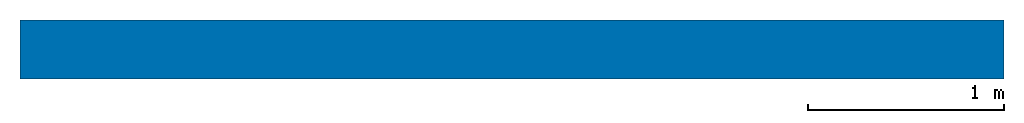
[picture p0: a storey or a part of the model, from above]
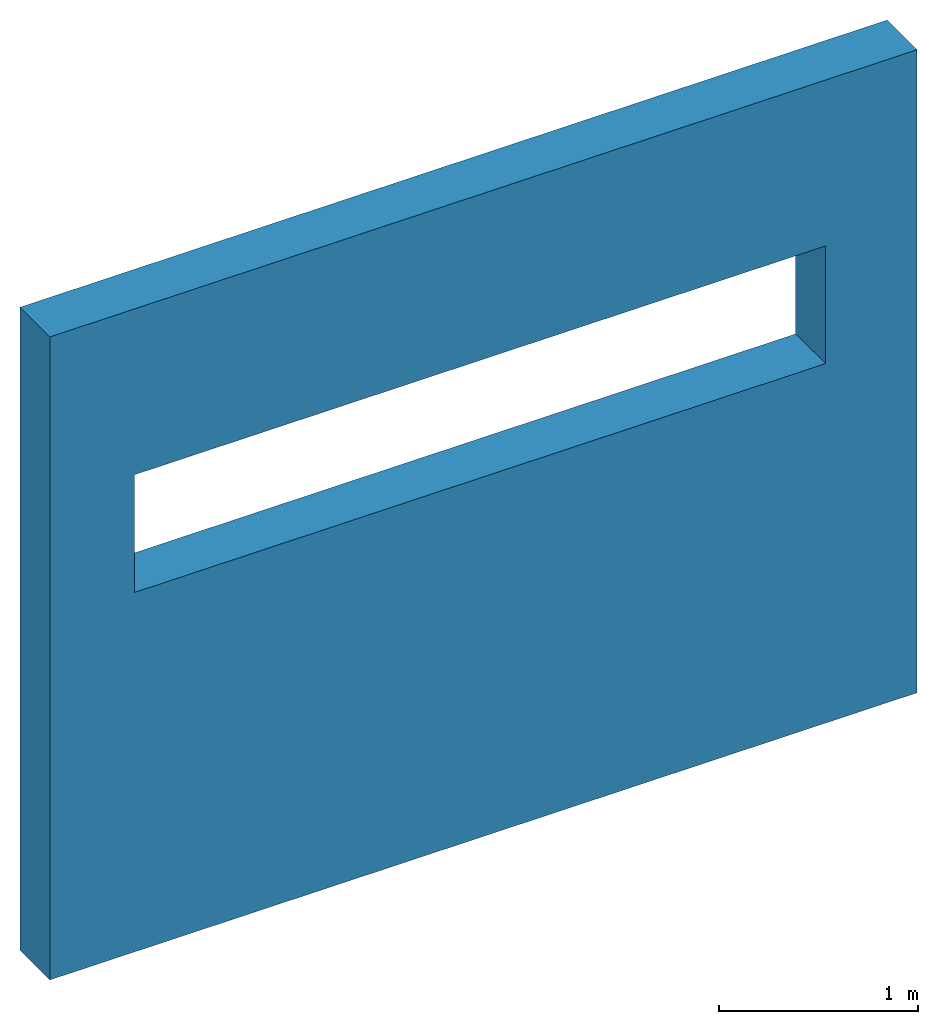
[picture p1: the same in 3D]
Properties of the parts of a building model (IFC2X3)

# File
Description: ViewDefinition [CoordinationView_V2.0, QuantityTakeOffAddOnView]
File name: P294-PE-ARQ_Moduls.ifc (Edited by Simplebim 8.2 SR1 - Evaluation)
Time: 2020-10-28T11:02:44
Written by: The EXPRESS Data Manager Version 5.02.0100.07 : 28 Aug 2013
Made in: 20191031_1115(x64) - Exporter 20.2.0.48 - Alternate UI 20.2.0.48

# IfcProject, P294
LongName: EDIFICI HOSPITALARI POLIVALENT Hospital Universitari Arnau de Vilanova; Phase: PROJECTE EXECUTIU

# IfcSite, Default
RefLatitude: 41, 36, 50, 998535; RefLongitude: 0, 37, 32, 890777; RefElevation: 175 m
Other - Project Address: Carrer de l'Arquitecte Gomà, 10 Lleida 25196; Project Number: P294; Category: Project Information; Project Status: PROJECTE EXECUTIU; Project Issue Date: SETEMBRE 2020; Client Name: SERVEI CATALÀ DE LA SALUT; Project Name: EDIFICI HOSPITALARI POLIVALENT Hospital Universitari Arnau de Vilanova
Identity Data - Autor 4: JOANA CORNUDELLA; Autor 2: MAXIMIÀ TORRUELLA; Autor 3: LUIS GOTOR; Autor 1: PATRICIO MARTÍNEZ; Workset: Project Info; Organization Description: Forward Thinking Healthcare Architecture; Author: PMMT Forward Thinking Healthcare Architecture; Organization Name: PMMT
Data - Colaborador 2: EINESA; Constructora: CONSTRUCTORA D'ARO; Colaborador 1: BIS STRUCTURES

# IfcBuilding
Pset_BuildingCommon - NumberOfStoreys: 6
Identity Data - Autor 4: JOANA CORNUDELLA; Autor 2: MAXIMIÀ TORRUELLA; Autor 3: LUIS GOTOR; Autor 1: PATRICIO MARTÍNEZ; Workset: Project Info; Organization Description: Forward Thinking Healthcare Architecture; Author: PMMT Forward Thinking Healthcare Architecture; Organization Name: PMMT
Other - Project Address: Carrer de l'Arquitecte Gomà, 10 Lleida 25196; Project Number: P294; Category: Project Information; Project Status: PROJECTE EXECUTIU; Project Issue Date: SETEMBRE 2020; Client Name: SERVEI CATALÀ DE LA SALUT; Project Name: EDIFICI HOSPITALARI POLIVALENT Hospital Universitari Arnau de Vilanova
Data - Colaborador 2: EINESA; Constructora: CONSTRUCTORA D'ARO; Colaborador 1: BIS STRUCTURES
Pset_ProductRequirements - Category: Project Information

# IfcBuildingStorey: Level:ARCH-NIV-General, P00
LongName: P00; Elevation: 0 m
Identity Data(Type) - Workset: Level Types; Type Name: ARCH-NIV-General
Other - Type Id: Level: ARCH-NIV-General; Type: Level: ARCH-NIV-General; Family and Type: Level: ARCH-NIV-General; Family: Level: ARCH-NIV-General; Category: Levels
Pset_ProductRequirements - Name: P00; Category: Levels
Pset_AirSideSystemInformation - Name: P00
Graphics(Type) - Symbol: ARCH-NIV-Etiqueta: 2mm; Line Pattern: ARCH-DASHDOT1; Symbol at End 1 Default: yes; Symbol at End 2 Default: no; Color: 8421504; Line Weight: 1
Constraints(Type) - Elevation Base: Project Base Point
Constraints - Elevation: 0 m
Dimensions - Computation Height: 0 m
Identity Data - Workset: A-000-DATUM; Edited by: Eipm02; Structural: no; Building Story: yes; Name: P00
Other(Type) - Category: Levels; Family Name: Level

# IfcWall: Basic Wall:P294-FAC-030, Basic Wall:P294-FAC-030:381034
In: P00
Type - PredefinedType: STANDARD; Material: ARCH-Gris 0.3 m
Type - Analytical Properties - Roughness: 3; Absorptance: 0.7
Type - Construction - Function: Exterior; Width: 0.3 m; Wrapping at Inserts: Do not wrap
Type - Graphics - Coarse Scale Fill Color: 8421504; Coarse Scale Fill Pattern: <Solid fill>
Type - Identity Data - Keynote: FBxx; Type Name: P294-FAC-030; Workset: Wall Types
Type - Materials and Finishes - Structural Material: ARCH-Gris
Type - Other - Category: Walls; Family Name: Basic Wall
Type - Pset_ElementShading - Roughness: 0.9144 m
Type - Pset_ProductRequirements - Category: Walls
Type - Pset_QuantityTakeOff - Reference: P294-FAC-030
Type - Pset_ReinforcementBarPitchOfWall - Reference: P294-FAC-030
Type - Pset_WallCommon - IsExternal: no; Reference: P294-FAC-030
Other - Type: Basic Wall: P294-FAC-030; Type Id: Basic Wall: P294-FAC-030; Family: Basic Wall: P294-FAC-030; Family and Type: Basic Wall: P294-FAC-030
Pset_WallCommon - LoadBearing: no; ExtendToStructure: no
Phasing - Phase Created: New Construction
ePset_SimplebimBasicQuantities - Volume, net (Simplebim): 5.06211 m3; Area, largest surface, net (Simplebim): 16.8737 m2; Area, side, net, average (Simplebim): 16.8737 m2; Area, side, net, smaller (Simplebim): 16.8737 m2; Area, side, net, larger (Simplebim): 16.8737 m2; Length (Simplebim): 5.02 m; Area, side, gross, smaller (Simplebim): 21.8039 m2; Area, side, gross, larger (Simplebim): 21.8039 m2; Area, side, gross, average (Simplebim): 21.8039 m2; Height (Simplebim): 3.935 m; Thickness (Simplebim): 0.3 m; Area, side, gross, AABB (Simplebim): 19.7537 m2
Identity Data - Edited by: Eipm02
Structural - Structural Usage: Non-bearing; Enable Analytical Model: no; Structural: no
ePset_LocationTool - Location 0: P00; Splitting: RESULT
Constraints - Base Constraint: Level: P00; Related to Mass: no; Room Bounding: yes; Base is Attached: no; Top is Attached: no; Location Line: Finish Face: Interior; Top Constraint: Level: PTC
